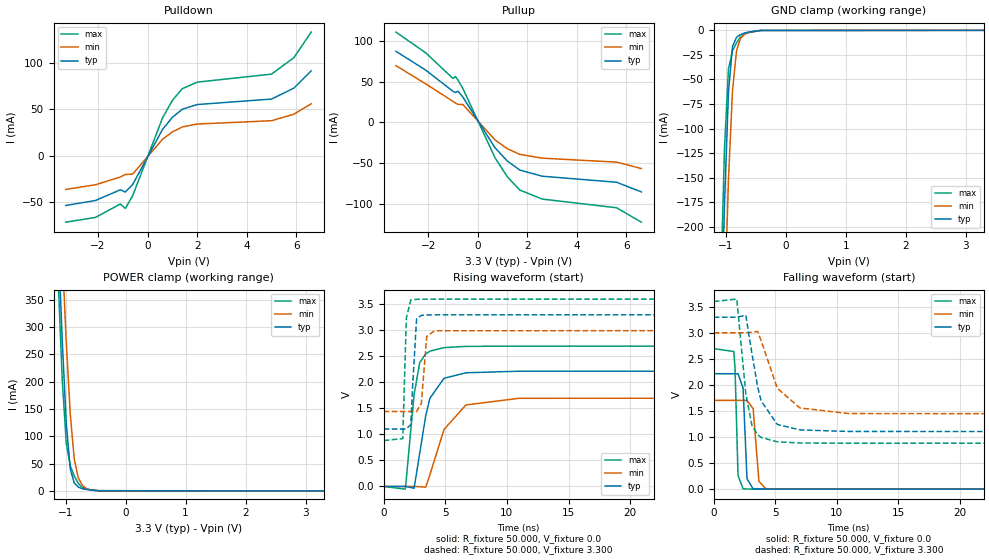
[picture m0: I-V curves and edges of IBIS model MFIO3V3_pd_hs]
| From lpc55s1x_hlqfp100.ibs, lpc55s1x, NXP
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|   Model MFIO3V3_pd_hs
[Model] MFIO3V3_pd_hs
Model_type I/O
Polarity   Non-Inverting
Enable   Active-Low
Vinl =  0.990V
Vinh =  2.310V
Vmeas =  1.650V
Cref =  0.0F
Rref =  100.000
Vref =  0.0V
C_comp   1.925pF   1.906pF   1.947pF
C_comp_pullup   1.145pF   1.141pF   1.152pF
C_comp_pulldown   0.641pF   0.633pF   0.647pF
[Model Spec]
Vinh   2.310V   2.100V   2.520V
Vinl   0.990V   0.900V   1.080V
Vmeas   1.650V   1.500V   1.800V
Vref   0.0V   0.0V   0.0V
Cref   0.0F   0.0F   0.0F
Rref   100.000   100.000   100.000
[Temperature Range]   25.000   0.125k   -40.000
[Voltage Range]   3.300V   3.000V   3.600V
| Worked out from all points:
|   slope of the pulldown table from 0 to 0.495 V, typ, clamps not added: 20.7 ohm
|   slope of the pullup table from 0 to 0.495 V, typ, clamps not added: 21.4 ohm
|   GND clamp passes 1 mA (typ) near -0.56 V on its own axis
|   POWER clamp passes 1 mA (typ) near -0.53 V on its own axis
|   rising waveform, R_fixture 50.000, V_fixture 0.0: 20-80 % time 1.05ns typ, 1.66ns min, 670ps max; typ from 0 V to 2.21 V
|   rising waveform, R_fixture 50.000, V_fixture 3.300: 20-80 % time 177ps typ, 247ps min, 146ps max; typ from 1.1 V to 3.3 V
|   falling waveform, R_fixture 50.000, V_fixture 0.0: 20-80 % time 203ps typ, 293ps min, 162ps max; typ from 2.21 V to 0 V
|   falling waveform, R_fixture 50.000, V_fixture 3.300: 20-80 % time 1.13ns typ, 1.67ns min, 744ps max; typ from 3.3 V to 1.1 V
[Pulldown]
|Voltage   I(typ)   I(min)   I(max)
-3.3V     -53.7mA    -36.43mA   -71.67mA
-2.1V     -48.29mA   -31.37mA   -66.51mA
-1.1V     -36.82mA   -23.05mA   -52.1mA
-900mV    -39.2mA    -20.39mA   -56.91mA
-600mV    -30.96mA   -19.83mA   -42.97mA
600mV     28.07mA    17.5mA     40.4mA
1V        41.17mA    25.53mA    59.41mA
1.4V      49.87mA    30.79mA    72.04mA
2V        54.93mA    33.94mA    79.03mA
5V        60.84mA    37.53mA    87.68mA
5.9V      72.62mA    44.52mA    105.4mA
6.6V      91.19mA    55.78mA    132.9mA
[Pullup]
|Voltage   I(typ)   I(min)   I(max)
-3.3V     87.16mA    69.54mA    110.7mA
-2.1V     64.12mA    47.22mA    85.31mA
-1V       38.1mA     25.85mA    53.88mA
-900mV    36.64mA    23.75mA    56.16mA
-800mV    38.25mA    22.02mA    51.93mA
-600mV    31.06mA    21.93mA    41.58mA
700mV     -31.25mA   -21.55mA   -43.56mA
1.2V      -47.6mA    -32.42mA   -66.97mA
1.7V      -58.52mA   -39.3mA    -83.05mA
2.6V      -66.01mA   -43.88mA   -94.06mA
5.6V      -73.4mA    -48.74mA   -104.7mA
6.6V      -85.32mA   -56.6mA    -122.4mA
[GND_clamp]
|Voltage   I(typ)   I(min)   I(max)
-3.3V     -7.222A    -7.177A    -7.278A
-1.089V   -337.1mA   -440.8mA   -274.1mA
-1.022V   -178.2mA   -284.2mA   -121mA
-955mV    -63.05mA   -151.6mA   -39.25mA
-888mV    -16.33mA   -61.34mA   -20.9mA
-821mV    -7.066mA   -20.84mA   -12.66mA
-754mV    -4.265mA   -8.157mA   -6.693mA
-687mV    -2.794mA   -3.896mA   -3.841mA
-620mV    -1.725mA   -1.894mA   -2.339mA
-419mV    -112.4uA   -138.2uA   -135uA
3.3V      0A         0A         0A
[POWER_clamp]
|Voltage   I(typ)   I(min)   I(max)
-3.3V     8.016A     7.986A     8.074A
-1.122V   463.8mA    614.4mA    385mA
-1.055V   276.3mA    435mA      203.9mA
-988mV    124.1mA    272.4mA    87.22mA
-921mV    40.03mA    140.2mA    45.68mA
-854mV    14.24mA    57.83mA    27.12mA
-787mV    6.921mA    23.8mA     13.77mA
-720mV    4.141mA    10.27mA    6.207mA
-653mV    2.682mA    4.42mA     3.699mA
-586mV    1.616mA    1.919mA    2.191mA
-452mV    346.9uA    411.9uA    422.9uA
3.3V      0A         0A         0A
[Ramp]
| variable   typ   min   max
dV/dt_r   1.328/1.048n   1.022/1.659n   1.617/0.670n
dV/dt_f   1.317/1.132n   0.935/1.671n   1.631/0.743n
R_load = 50.000
[Rising Waveform]
R_fixture= 50.000
V_fixture= 0.0
V_fixture_min= 0.0
V_fixture_max= 0.0
|time   V(typ)   V(min)   V(max)
0s        11.38nV    124.8nV    46.5nV
1.76ns    11.77uV    -454.5nV   -52.39mV
2.47ns    -34.09mV   72.05uV    1.767V
2.93ns    642.6mV    -5.154mV   2.378V
3.41ns    1.355V     -14.68mV   2.545V
3.75ns    1.693V     224.8mV    2.598V
4.9ns     2.078V     1.096V     2.667V
6.67ns    2.183V     1.564V     2.69V
10.95ns   2.213V     1.693V     2.695V
100ns     2.214V     1.703V     2.695V
[Rising Waveform]
R_fixture= 50.000
V_fixture= 3.300
V_fixture_min= 3.000
V_fixture_max= 3.600
|time   V(typ)   V(min)   V(max)
0s        1.105V     1.44V      880.4mV
1.55ns    1.105V     1.44V      919.2mV
1.84ns    1.105V     1.44V      3.234V
2.2ns     1.188V     1.44V      3.582V
2.35ns    1.923V     1.44V      3.589V
2.67ns    3.216V     1.439V     3.594V
3.06ns    3.287V     1.596V     3.596V
3.49ns    3.293V     2.878V     3.597V
4.12ns    3.296V     2.99V      3.598V
100ns     3.299V     2.999V     3.599V
[Falling Waveform]
R_fixture= 50.000
V_fixture= 0.0
V_fixture_min= 0.0
V_fixture_max= 0.0
|time   V(typ)   V(min)   V(max)
0s        2.214V     1.703V     2.695V
1.63ns    2.214V     1.703V     2.64V
1.73ns    2.214V     1.703V     2.3V
1.97ns    2.214V     1.703V     263mV
2.38ns    1.941V     1.702V     7.184mV
2.7ns     199.7mV    1.703V     3.012mV
3.2ns     7.193mV    1.543V     1.541mV
3.67ns    2.766mV    149.1mV    968.7uV
4.23ns    1.498mV    7.536mV    571.2uV
100ns     15.88nV    132.9nV    49.27nV
[Falling Waveform]
R_fixture= 50.000
V_fixture= 3.300
V_fixture_min= 3.000
V_fixture_max= 3.600
|time   V(typ)   V(min)   V(max)
0s        3.299V     2.999V     3.599V
1.87ns    3.299V     2.999V     3.646V
2.6ns     3.336V     2.999V     1.836V
3.1ns     2.603V     3.008V     1.222V
3.57ns    1.958V     3.025V     1.042V
3.85ns    1.693V     2.847V     992.4mV
5.16ns    1.242V     1.936V     908.2mV
7ns       1.136V     1.557V     885.7mV
10.97ns   1.107V     1.45V      880.6mV
100ns     1.105V     1.44V      880.4mV
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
